VERSION 5.7 ;
  NOWIREEXTENSIONATPIN ON ;
  DIVIDERCHAR "/" ;
  BUSBITCHARS "[]" ;
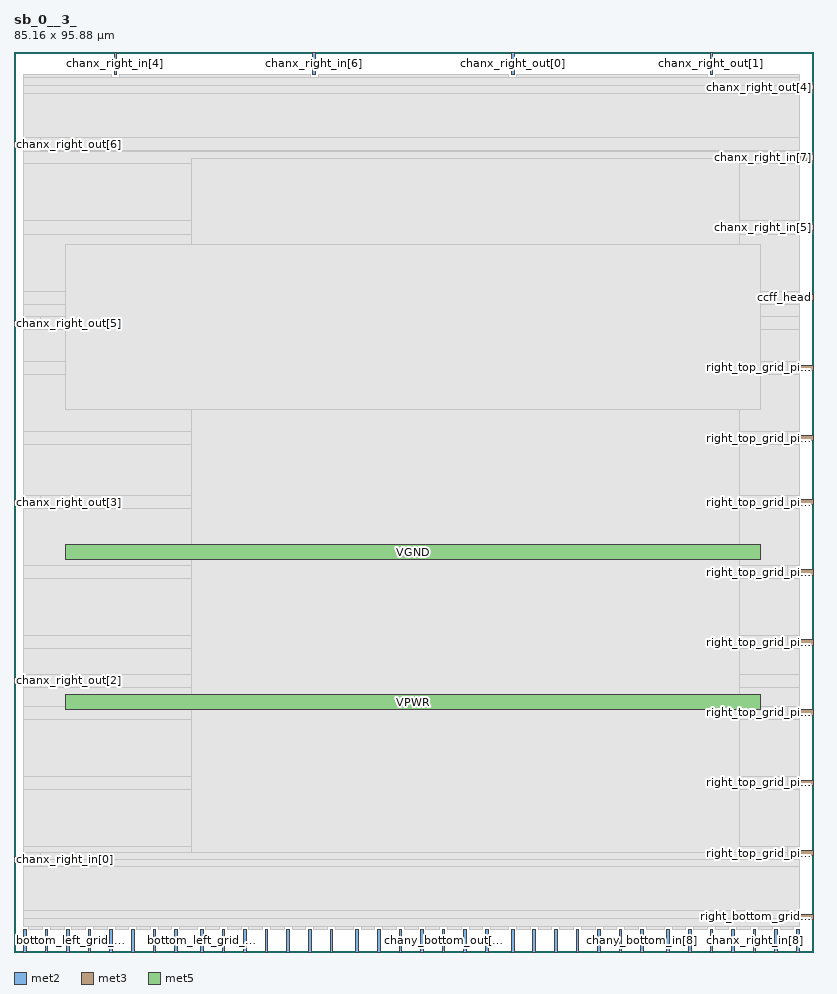
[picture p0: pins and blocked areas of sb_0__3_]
MACRO sb_0__3_
  CLASS BLOCK ;
  FOREIGN sb_0__3_ ;
  ORIGIN 0.000 0.000 ;
  SIZE 85.160 BY 95.880 ;
  PIN bottom_left_grid_pin_11_
    DIRECTION INPUT ;
    PORT
      LAYER met2 ;
        RECT 14.810 0.000 15.090 2.400 ;
    END
  END bottom_left_grid_pin_11_
  PIN bottom_left_grid_pin_13_
    DIRECTION INPUT ;
    PORT
      LAYER met2 ;
        RECT 17.110 0.000 17.390 2.400 ;
    END
  END bottom_left_grid_pin_13_
  PIN bottom_left_grid_pin_15_
    DIRECTION INPUT ;
    PORT
      LAYER met2 ;
        RECT 19.870 0.000 20.150 2.400 ;
    END
  END bottom_left_grid_pin_15_
  PIN bottom_left_grid_pin_1_
    DIRECTION INPUT ;
    PORT
      LAYER met2 ;
        RECT 3.310 0.000 3.590 2.400 ;
    END
  END bottom_left_grid_pin_1_
  PIN bottom_left_grid_pin_3_
    DIRECTION INPUT ;
    PORT
      LAYER met2 ;
        RECT 5.610 0.000 5.890 2.400 ;
    END
  END bottom_left_grid_pin_3_
  PIN bottom_left_grid_pin_5_
    DIRECTION INPUT ;
    PORT
      LAYER met2 ;
        RECT 7.910 0.000 8.190 2.400 ;
    END
  END bottom_left_grid_pin_5_
  PIN bottom_left_grid_pin_7_
    DIRECTION INPUT ;
    PORT
      LAYER met2 ;
        RECT 10.210 0.000 10.490 2.400 ;
    END
  END bottom_left_grid_pin_7_
  PIN bottom_left_grid_pin_9_
    DIRECTION INPUT ;
    PORT
      LAYER met2 ;
        RECT 12.510 0.000 12.790 2.400 ;
    END
  END bottom_left_grid_pin_9_
  PIN bottom_right_grid_pin_11_
    DIRECTION INPUT ;
    PORT
      LAYER met2 ;
        RECT 69.550 0.000 69.830 2.400 ;
    END
  END bottom_right_grid_pin_11_
  PIN ccff_head
    DIRECTION INPUT ;
    PORT
      LAYER met3 ;
        RECT 82.760 69.400 85.160 70.000 ;
    END
  END ccff_head
  PIN ccff_tail
    DIRECTION OUTPUT TRISTATE ;
    PORT
      LAYER met2 ;
        RECT 1.010 0.000 1.290 2.400 ;
    END
  END ccff_tail
  PIN chanx_right_in[0]
    DIRECTION INPUT ;
    PORT
      LAYER met3 ;
        RECT 0.000 9.560 2.400 10.160 ;
    END
  END chanx_right_in[0]
  PIN chanx_right_in[1]
    DIRECTION INPUT ;
    PORT
      LAYER met2 ;
        RECT 71.850 0.000 72.130 2.400 ;
    END
  END chanx_right_in[1]
  PIN chanx_right_in[2]
    DIRECTION INPUT ;
    PORT
      LAYER met2 ;
        RECT 74.150 0.000 74.430 2.400 ;
    END
  END chanx_right_in[2]
  PIN chanx_right_in[3]
    DIRECTION INPUT ;
    PORT
      LAYER met2 ;
        RECT 76.450 0.000 76.730 2.400 ;
    END
  END chanx_right_in[3]
  PIN chanx_right_in[4]
    DIRECTION INPUT ;
    PORT
      LAYER met2 ;
        RECT 10.670 93.480 10.950 95.880 ;
    END
  END chanx_right_in[4]
  PIN chanx_right_in[5]
    DIRECTION INPUT ;
    PORT
      LAYER met3 ;
        RECT 82.760 76.880 85.160 77.480 ;
    END
  END chanx_right_in[5]
  PIN chanx_right_in[6]
    DIRECTION INPUT ;
    PORT
      LAYER met2 ;
        RECT 31.830 93.480 32.110 95.880 ;
    END
  END chanx_right_in[6]
  PIN chanx_right_in[7]
    DIRECTION INPUT ;
    PORT
      LAYER met3 ;
        RECT 82.760 84.360 85.160 84.960 ;
    END
  END chanx_right_in[7]
  PIN chanx_right_in[8]
    DIRECTION INPUT ;
    PORT
      LAYER met2 ;
        RECT 78.750 0.000 79.030 2.400 ;
    END
  END chanx_right_in[8]
  PIN chanx_right_out[0]
    DIRECTION OUTPUT TRISTATE ;
    PORT
      LAYER met2 ;
        RECT 52.990 93.480 53.270 95.880 ;
    END
  END chanx_right_out[0]
  PIN chanx_right_out[1]
    DIRECTION OUTPUT TRISTATE ;
    PORT
      LAYER met2 ;
        RECT 74.150 93.480 74.430 95.880 ;
    END
  END chanx_right_out[1]
  PIN chanx_right_out[2]
    DIRECTION OUTPUT TRISTATE ;
    PORT
      LAYER met3 ;
        RECT 0.000 28.600 2.400 29.200 ;
    END
  END chanx_right_out[2]
  PIN chanx_right_out[3]
    DIRECTION OUTPUT TRISTATE ;
    PORT
      LAYER met3 ;
        RECT 0.000 47.640 2.400 48.240 ;
    END
  END chanx_right_out[3]
  PIN chanx_right_out[4]
    DIRECTION OUTPUT TRISTATE ;
    PORT
      LAYER met3 ;
        RECT 82.760 91.840 85.160 92.440 ;
    END
  END chanx_right_out[4]
  PIN chanx_right_out[5]
    DIRECTION OUTPUT TRISTATE ;
    PORT
      LAYER met3 ;
        RECT 0.000 66.680 2.400 67.280 ;
    END
  END chanx_right_out[5]
  PIN chanx_right_out[6]
    DIRECTION OUTPUT TRISTATE ;
    PORT
      LAYER met3 ;
        RECT 0.000 85.720 2.400 86.320 ;
    END
  END chanx_right_out[6]
  PIN chanx_right_out[7]
    DIRECTION OUTPUT TRISTATE ;
    PORT
      LAYER met2 ;
        RECT 81.050 0.000 81.330 2.400 ;
    END
  END chanx_right_out[7]
  PIN chanx_right_out[8]
    DIRECTION OUTPUT TRISTATE ;
    PORT
      LAYER met2 ;
        RECT 83.350 0.000 83.630 2.400 ;
    END
  END chanx_right_out[8]
  PIN chany_bottom_in[0]
    DIRECTION INPUT ;
    PORT
      LAYER met2 ;
        RECT 47.930 0.000 48.210 2.400 ;
    END
  END chany_bottom_in[0]
  PIN chany_bottom_in[1]
    DIRECTION INPUT ;
    PORT
      LAYER met2 ;
        RECT 50.230 0.000 50.510 2.400 ;
    END
  END chany_bottom_in[1]
  PIN chany_bottom_in[2]
    DIRECTION INPUT ;
    PORT
      LAYER met2 ;
        RECT 52.990 0.000 53.270 2.400 ;
    END
  END chany_bottom_in[2]
  PIN chany_bottom_in[3]
    DIRECTION INPUT ;
    PORT
      LAYER met2 ;
        RECT 55.290 0.000 55.570 2.400 ;
    END
  END chany_bottom_in[3]
  PIN chany_bottom_in[4]
    DIRECTION INPUT ;
    PORT
      LAYER met2 ;
        RECT 57.590 0.000 57.870 2.400 ;
    END
  END chany_bottom_in[4]
  PIN chany_bottom_in[5]
    DIRECTION INPUT ;
    PORT
      LAYER met2 ;
        RECT 59.890 0.000 60.170 2.400 ;
    END
  END chany_bottom_in[5]
  PIN chany_bottom_in[6]
    DIRECTION INPUT ;
    PORT
      LAYER met2 ;
        RECT 62.190 0.000 62.470 2.400 ;
    END
  END chany_bottom_in[6]
  PIN chany_bottom_in[7]
    DIRECTION INPUT ;
    PORT
      LAYER met2 ;
        RECT 64.490 0.000 64.770 2.400 ;
    END
  END chany_bottom_in[7]
  PIN chany_bottom_in[8]
    DIRECTION INPUT ;
    PORT
      LAYER met2 ;
        RECT 66.790 0.000 67.070 2.400 ;
    END
  END chany_bottom_in[8]
  PIN chany_bottom_out[0]
    DIRECTION OUTPUT TRISTATE ;
    PORT
      LAYER met2 ;
        RECT 26.770 0.000 27.050 2.400 ;
    END
  END chany_bottom_out[0]
  PIN chany_bottom_out[1]
    DIRECTION OUTPUT TRISTATE ;
    PORT
      LAYER met2 ;
        RECT 29.070 0.000 29.350 2.400 ;
    END
  END chany_bottom_out[1]
  PIN chany_bottom_out[2]
    DIRECTION OUTPUT TRISTATE ;
    PORT
      LAYER met2 ;
        RECT 31.370 0.000 31.650 2.400 ;
    END
  END chany_bottom_out[2]
  PIN chany_bottom_out[3]
    DIRECTION OUTPUT TRISTATE ;
    PORT
      LAYER met2 ;
        RECT 33.670 0.000 33.950 2.400 ;
    END
  END chany_bottom_out[3]
  PIN chany_bottom_out[4]
    DIRECTION OUTPUT TRISTATE ;
    PORT
      LAYER met2 ;
        RECT 36.430 0.000 36.710 2.400 ;
    END
  END chany_bottom_out[4]
  PIN chany_bottom_out[5]
    DIRECTION OUTPUT TRISTATE ;
    PORT
      LAYER met2 ;
        RECT 38.730 0.000 39.010 2.400 ;
    END
  END chany_bottom_out[5]
  PIN chany_bottom_out[6]
    DIRECTION OUTPUT TRISTATE ;
    PORT
      LAYER met2 ;
        RECT 41.030 0.000 41.310 2.400 ;
    END
  END chany_bottom_out[6]
  PIN chany_bottom_out[7]
    DIRECTION OUTPUT TRISTATE ;
    PORT
      LAYER met2 ;
        RECT 43.330 0.000 43.610 2.400 ;
    END
  END chany_bottom_out[7]
  PIN chany_bottom_out[8]
    DIRECTION OUTPUT TRISTATE ;
    PORT
      LAYER met2 ;
        RECT 45.630 0.000 45.910 2.400 ;
    END
  END chany_bottom_out[8]
  PIN pReset
    DIRECTION INPUT ;
    PORT
      LAYER met2 ;
        RECT 24.470 0.000 24.750 2.400 ;
    END
  END pReset
  PIN prog_clk
    DIRECTION INPUT ;
    PORT
      LAYER met2 ;
        RECT 22.170 0.000 22.450 2.400 ;
    END
  END prog_clk
  PIN right_bottom_grid_pin_12_
    DIRECTION INPUT ;
    PORT
      LAYER met3 ;
        RECT 82.760 3.440 85.160 4.040 ;
    END
  END right_bottom_grid_pin_12_
  PIN right_top_grid_pin_11_
    DIRECTION INPUT ;
    PORT
      LAYER met3 ;
        RECT 82.760 25.200 85.160 25.800 ;
    END
  END right_top_grid_pin_11_
  PIN right_top_grid_pin_13_
    DIRECTION INPUT ;
    PORT
      LAYER met3 ;
        RECT 82.760 17.720 85.160 18.320 ;
    END
  END right_top_grid_pin_13_
  PIN right_top_grid_pin_15_
    DIRECTION INPUT ;
    PORT
      LAYER met3 ;
        RECT 82.760 10.240 85.160 10.840 ;
    END
  END right_top_grid_pin_15_
  PIN right_top_grid_pin_1_
    DIRECTION INPUT ;
    PORT
      LAYER met3 ;
        RECT 82.760 61.920 85.160 62.520 ;
    END
  END right_top_grid_pin_1_
  PIN right_top_grid_pin_3_
    DIRECTION INPUT ;
    PORT
      LAYER met3 ;
        RECT 82.760 54.440 85.160 55.040 ;
    END
  END right_top_grid_pin_3_
  PIN right_top_grid_pin_5_
    DIRECTION INPUT ;
    PORT
      LAYER met3 ;
        RECT 82.760 47.640 85.160 48.240 ;
    END
  END right_top_grid_pin_5_
  PIN right_top_grid_pin_7_
    DIRECTION INPUT ;
    PORT
      LAYER met3 ;
        RECT 82.760 40.160 85.160 40.760 ;
    END
  END right_top_grid_pin_7_
  PIN right_top_grid_pin_9_
    DIRECTION INPUT ;
    PORT
      LAYER met3 ;
        RECT 82.760 32.680 85.160 33.280 ;
    END
  END right_top_grid_pin_9_
  PIN VPWR
    DIRECTION INPUT ;
    USE POWER ;
    PORT
      LAYER met5 ;
        RECT 5.520 25.820 79.580 27.420 ;
    END
  END VPWR
  PIN VGND
    DIRECTION INPUT ;
    USE GROUND ;
    PORT
      LAYER met5 ;
        RECT 5.520 41.800 79.580 43.400 ;
    END
  END VGND
  OBS
      LAYER li1 ;
        RECT 4.745 10.795 79.580 84.405 ;
      LAYER met1 ;
        RECT 3.290 2.760 79.580 84.560 ;
      LAYER met2 ;
        RECT 1.010 93.200 10.390 93.480 ;
        RECT 11.230 93.200 31.550 93.480 ;
        RECT 32.390 93.200 52.710 93.480 ;
        RECT 53.550 93.200 73.870 93.480 ;
        RECT 74.710 93.200 83.630 93.480 ;
        RECT 1.010 2.680 83.630 93.200 ;
        RECT 1.570 2.400 3.030 2.680 ;
        RECT 3.870 2.400 5.330 2.680 ;
        RECT 6.170 2.400 7.630 2.680 ;
        RECT 8.470 2.400 9.930 2.680 ;
        RECT 10.770 2.400 12.230 2.680 ;
        RECT 13.070 2.400 14.530 2.680 ;
        RECT 15.370 2.400 16.830 2.680 ;
        RECT 17.670 2.400 19.590 2.680 ;
        RECT 20.430 2.400 21.890 2.680 ;
        RECT 22.730 2.400 24.190 2.680 ;
        RECT 25.030 2.400 26.490 2.680 ;
        RECT 27.330 2.400 28.790 2.680 ;
        RECT 29.630 2.400 31.090 2.680 ;
        RECT 31.930 2.400 33.390 2.680 ;
        RECT 34.230 2.400 36.150 2.680 ;
        RECT 36.990 2.400 38.450 2.680 ;
        RECT 39.290 2.400 40.750 2.680 ;
        RECT 41.590 2.400 43.050 2.680 ;
        RECT 43.890 2.400 45.350 2.680 ;
        RECT 46.190 2.400 47.650 2.680 ;
        RECT 48.490 2.400 49.950 2.680 ;
        RECT 50.790 2.400 52.710 2.680 ;
        RECT 53.550 2.400 55.010 2.680 ;
        RECT 55.850 2.400 57.310 2.680 ;
        RECT 58.150 2.400 59.610 2.680 ;
        RECT 60.450 2.400 61.910 2.680 ;
        RECT 62.750 2.400 64.210 2.680 ;
        RECT 65.050 2.400 66.510 2.680 ;
        RECT 67.350 2.400 69.270 2.680 ;
        RECT 70.110 2.400 71.570 2.680 ;
        RECT 72.410 2.400 73.870 2.680 ;
        RECT 74.710 2.400 76.170 2.680 ;
        RECT 77.010 2.400 78.470 2.680 ;
        RECT 79.310 2.400 80.770 2.680 ;
        RECT 81.610 2.400 83.070 2.680 ;
      LAYER met3 ;
        RECT 0.985 91.440 82.360 92.305 ;
        RECT 0.985 86.720 83.655 91.440 ;
        RECT 2.800 85.360 83.655 86.720 ;
        RECT 2.800 85.320 82.360 85.360 ;
        RECT 0.985 83.960 82.360 85.320 ;
        RECT 0.985 77.880 83.655 83.960 ;
        RECT 0.985 76.480 82.360 77.880 ;
        RECT 0.985 70.400 83.655 76.480 ;
        RECT 0.985 69.000 82.360 70.400 ;
        RECT 0.985 67.680 83.655 69.000 ;
        RECT 2.800 66.280 83.655 67.680 ;
        RECT 0.985 62.920 83.655 66.280 ;
        RECT 0.985 61.520 82.360 62.920 ;
        RECT 0.985 55.440 83.655 61.520 ;
        RECT 0.985 54.040 82.360 55.440 ;
        RECT 0.985 48.640 83.655 54.040 ;
        RECT 2.800 47.240 82.360 48.640 ;
        RECT 0.985 41.160 83.655 47.240 ;
        RECT 0.985 39.760 82.360 41.160 ;
        RECT 0.985 33.680 83.655 39.760 ;
        RECT 0.985 32.280 82.360 33.680 ;
        RECT 0.985 29.600 83.655 32.280 ;
        RECT 2.800 28.200 83.655 29.600 ;
        RECT 0.985 26.200 83.655 28.200 ;
        RECT 0.985 24.800 82.360 26.200 ;
        RECT 0.985 18.720 83.655 24.800 ;
        RECT 0.985 17.320 82.360 18.720 ;
        RECT 0.985 11.240 83.655 17.320 ;
        RECT 0.985 10.560 82.360 11.240 ;
        RECT 2.800 9.840 82.360 10.560 ;
        RECT 2.800 9.160 83.655 9.840 ;
        RECT 0.985 4.440 83.655 9.160 ;
        RECT 0.985 3.575 82.360 4.440 ;
      LAYER met4 ;
        RECT 18.910 10.640 77.285 84.560 ;
      LAYER met5 ;
        RECT 5.520 57.780 79.580 75.360 ;
  END
END sb_0__3_
END LIBRARY

